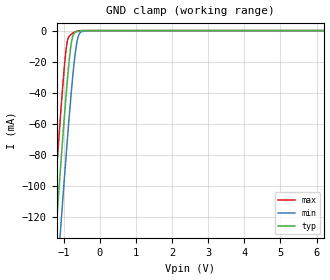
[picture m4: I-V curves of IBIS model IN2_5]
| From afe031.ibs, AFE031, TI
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|   IN2 5V Model
[Model]  IN2_5
Model_type Input
Vinl = 1.5
Vinh = 3.5
|   typ   min   max
|   (nom PVT)   (Fast PVT)   (slow PVT)
C_comp   8.5997880e-13  7.5144900e-13  1.0683370e-12
| Where   nom PVT is  Nominal Process, 5V, 52C
|   Fast PVT is Strong Process, 5.5V, -40C
|   Slow PVT is Weak Process, 4.5V, 150C
[Voltage Range]   5   4.5   5.5
[Temperature Range]   52   150   -40
[Power Clamp Reference]   5   4.5   5.5
[GND Clamp Reference]   0   0   0
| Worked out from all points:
|   GND clamp passes 1 mA (typ) near -0.68 V on its own axis
[GND Clamp]
|   Voltage   I(typ)   I(min)   I(max)
-5V       -1.452A    -1.471A    -1.441A
-1.363V   -178.7mA   -217.8mA   -145.9mA
-1.298V   -156.9mA   -196.2mA   -123.5mA
-1.217V   -130.1mA   -170mA     -96.4mA
-1.092V   -89.47mA   -129.6mA   -55.5mA
-979.9mV  -54.67mA   -94.45mA   -22.43mA
-921.5mV  -37.82mA   -76.87mA   -9.754mA
-788.5mV  -7.817mA   -38.95mA   -2.309mA
-647.5mV  -767.2uA   -9.042mA   -394uA
-561mV    -354uA     -1.782mA   -137.6uA
-352.6mV  -19.74uA   -18.32uA   -23.73uA
10V       0A         0A         0A
[POWER Clamp]
|   SCR cell for ESD function. Effects occurr above VDD x 2
|   Voltage   I(typ)   I(min)   I(max)
-5V       0A         0A         0A
0V        0A         0A         0A
10V       0A         0A         0A
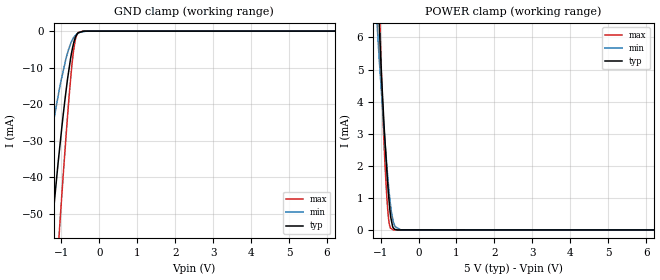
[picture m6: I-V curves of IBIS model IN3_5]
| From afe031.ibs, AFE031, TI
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|   IN3 5V Model
[Model] IN3_5
Model_type Input
Vinl = 1.5
Vinh = 3.5
|   typ   min   max
|   (nom PVT)   (Fast PVT)   (slow PVT)
C_comp   2.4967580e-12  1.9458590e-12  3.0425350e-12
| Where   nom PVT is  Nominal Process, 5V, 52C
|   Fast PVT is Strong Process, 5.5V, -40C
|   Slow PVT is Weak Process, 4.5V, 150C
[Voltage Range]   5   4.5   5.5
[Temperature Range]   52   150   -40
[Power Clamp Reference]   5   4.5   5.5
[GND Clamp Reference]   0   0   0
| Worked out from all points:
|   GND clamp passes 1 mA (typ) near -0.60 V on its own axis
|   POWER clamp passes 1 mA (typ) near -0.78 V on its own axis
[GND Clamp]
|   Voltage   I(typ)   I(min)   I(max)
-5V       -570.3mA   -388.6mA   -720mA
-1.705V   -109.7mA   -60.4mA    -162.3mA
-1.555V   -90.57mA   -48.68mA   -137mA
-1.259V   -54.9mA    -28.09mA   -87.57mA
-1.08V    -35.38mA   -17.42mA   -58.92mA
-1.045V   -31.94mA   -15.43mA   -53.42mA
-850.2mV  -14.08mA   -6.45mA    -24.89mA
-723.3mV  -5.492mA   -2.668mA   -9.289mA
-685mV    -3.657mA   -1.905mA   -5.728mA
-639.5mV  -1.962mA   -1.316mA   -2.701mA
-555.3mV  -436.4uA   -565.7uA   -380.8uA
10V       0A         0A         0A
[POWER Clamp]
|   Voltage   I(typ)   I(min)   I(max)
-5V       168.7mA    134.5mA    216.2mA
-1.1V     8.477mA    6.595mA    10.08mA
-1.054V   6.977mA    5.675mA    8.034mA
-1.029V   6.245mA    5.205mA    6.912mA
-1.013V   5.809mA    4.923mA    6.241mA
-925.6mV  3.647mA    3.387mA    3.134mA
-836.8mV  1.869mA    2.028mA    1.047mA
-769.8mV  812.1uA    1.114mA    178.2uA
-733.4mV  400.6uA    729.6uA    53.42uA
-662.5mV  60.65uA    242.4uA    1.487uA
-468.4mV  1.579uA    2.58uA     1.46uA
10V       0A         0A         0A
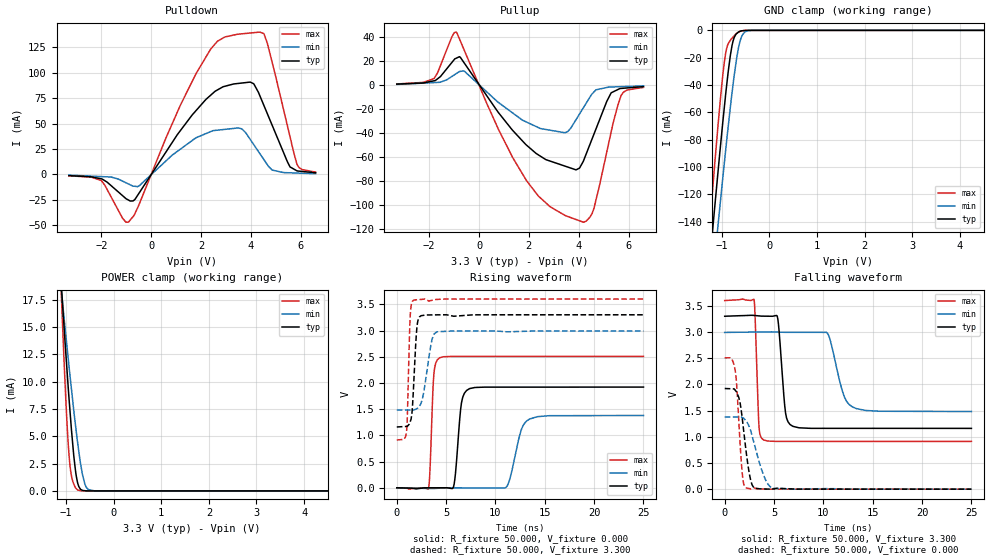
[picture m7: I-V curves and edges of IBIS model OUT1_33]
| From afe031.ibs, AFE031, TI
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|   OUT1 3.3V Model
[Model]  OUT1_33
Model_type   3-state
Polarity   Non-Inverting
Enable   Active-Low
Vmeas = 1.65
Vref = 1.65
Cref = 15pF
Rref = 50
| variable   typ   min   max
|   (nom PVT)   (fast PVT)   (slow PVT)
|C_comp Output in tri-state
|C_comp   1.8415600e-12  1.4370100e-12  2.2641990e-12
|C_comp Output High
C_comp   2.0065070e-12  1.8519680e-12  2.9695770e-12
|C_comp Output Low
|C_comp   1.8415600e-12  1.4370100e-12  2.2641990e-12
| Where   nom PVT is  Nominal Process, 3.3V, 52C
|   Fast PVT is Strong Process, 3.6V, -40C
|   Slow PVT is Weak Process, 3.0V, 150C
[Voltage Range]   3.3   3   3.6
[Temperature Range]   52   150   -40
[Pullup Reference]   3.3   3   3.6
[Pulldown Reference]   0   0   0
[Power Clamp Reference]   3.3   3   3.6
[GND Clamp Reference]   0   0   0
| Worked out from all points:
|   slope of the pulldown table from 0 to 0.495 V, typ, clamps not added: 26.7 ohm
|   slope of the pullup table from 0 to 0.495 V, typ, clamps not added: 33.2 ohm
|   GND clamp passes 1 mA (typ) near -0.64 V on its own axis
|   POWER clamp passes 1 mA (typ) near -0.77 V on its own axis
|   falling waveform, R_fixture 50.000, V_fixture 3.300: 20-80 % time 513ps typ, 1.18ns min, 290ps max; typ from 3.3 V to 1.16 V
|   rising waveform, R_fixture 50.000, V_fixture 0.000: 20-80 % time 500ps typ, 1.02ns min, 299ps max; typ from 0 V to 1.92 V
|   rising waveform, R_fixture 50.000, V_fixture 3.300: 20-80 % time 361ps typ, 734ps min, 231ps max; typ from 1.16 V to 3.3 V
|   falling waveform, R_fixture 50.000, V_fixture 0.000: 20-80 % time 765ps typ, 1.27ns min, 485ps max; typ from 1.92 V to 0 V
[Pulldown]
|   Voltage   I(typ)   I(min)   I(max)
-3.3V     -1.148mA   -651.7uA   -1.255mA
-2.005V   -4.236mA   -2.065mA   -5.91mA
-909.6mV  -25.1mA    -9.305mA   -46.78mA
-491mV    -18.61mA   -11.37mA   -30.01mA
1.155V    42.47mA    24.53mA    67mA
2.371V    77.45mA    41.9mA     122.4mA
3.642V    89.82mA    44.8mA     138.1mA
4.36V     77.57mA    20.63mA    139.9mA
4.66V     59.93mA    9.744mA    129.2mA
5.574V    7.463mA    1.637mA    37.03mA
5.855V    3.549mA    1.397mA    9.994mA
6.6V      1.672mA    769.8uA    2.368mA
[GND Clamp]
|   Voltage   I(typ)   I(min)   I(max)
-3.3V     -996.4mA   -974.3mA   -1.072A
-1.261V   -172mA     -207mA     -145.4mA
-1.196V   -146.9mA   -183.4mA   -117.3mA
-1.079V   -102.9mA   -142.1mA   -68.97mA
-980.7mV  -67.24mA   -108mA     -32.73mA
-918mV    -45.98mA   -87.03mA   -16.26mA
-824mV    -18.83mA   -56.93mA   -7.391mA
-768.6mV  -8.309mA   -40.63mA   -5.048mA
-620mV    -799.1uA   -8.237mA   -684.1uA
-508.1mV  -113.2uA   -1.039mA   -54.85uA
-368.2mV  -29.98uA   -33.32uA   -53.77uA
6.6V      0A         0A         0A
[Pullup]
|   Voltage   I(typ)   I(min)   I(max)
-3.3V     821.6uA    560.4uA    966.4uA
-1.811V   3.556mA    2.098mA    5.376mA
-918mV    22.37mA    9.531mA    44.13mA
-575.9mV  17.9mA     11.38mA    28.21mA
792.2mV   -23.21mA   -14.65mA   -37.35mA
1.893V    -49.73mA   -30.62mA   -79.08mA
3.448V    -67.4mA    -39.59mA   -108.4mA
4.189V    -63.19mA   -18.8mA    -114.1mA
4.609V    -40.93mA   -5.755mA   -102.7mA
5.3V      -6.532mA   -1.562mA   -39.17mA
5.693V    -2.774mA   -1.289mA   -9.028mA
6.6V      -1.247mA   -664.9uA   -1.876mA
[POWER Clamp]
|   Voltage   I(typ)   I(min)   I(max)
-3.3V     184.1mA    127.9mA    289.4mA
-1.099V   18.8mA     18.35mA    17.9mA
-1.077V   17.34mA    17.4mA     15.64mA
-1V       12.29mA    14.04mA    7.901mA
-934.8mV  8.291mA    11.26mA    3.127mA
-878mV    5.172mA    8.968mA    1.198mA
-802.2mV  1.867mA    6.031mA    289uA
-759.4mV  781.9uA    4.492mA    92.02uA
-659.6mV  65.94uA    1.591mA    7.295uA
-603.6mV  19.84uA    621.1uA    7.239uA
-399.7mV  3.531uA    3.881uA    7.034uA
6.6V      0A         0A         0A
[Ramp]
R_load = 50
|   typ   min   max
dV/dt_r   1.15238/4.93956e-010  0.827469/1.00739e-009   1.50375/2.99169e-010
dV/dt_f   1.28388/5.1154e-010   0.922043/1.17816e-009   1.6132/2.87325e-010
[Falling Waveform]
R_fixture = 50.000
V_fixture = 3.300
V_fixture_min = 3.000
V_fixture_max = 3.600
C_fixture = 0.000
|  time   V(typ)   V(min)   V(max)
0s        3.3V       2.991V     3.6V
2.977ns   3.315V     2.998V     3.617V
3.478ns   3.307V     2.999V     1.19V
3.931ns   3.302V     3V         940.6mV
5.337ns   3.291V     2.999V     911.9mV
6.164ns   1.46V      2.993V     911.9mV
6.901ns   1.199V     2.993V     911.8mV
10.41ns   1.161V     2.977V     911.7mV
12.93ns   1.161V     1.572V     911.7mV
25ns      1.16V      1.482V     911.3mV
[Rising Waveform]
R_fixture = 50.000
V_fixture = 0.000
V_fixture_min = 0.000
V_fixture_max = 0.000
C_fixture = 0.000
|  time   V(typ)   V(min)   V(max)
0s        1.734nV    17.7nV     538pV
3.215ns   -590.1uV   -12.93mV   -15.34mV
3.754ns   -338.2uV   -13.77mV   2.157V
4.351ns   -59.32uV   -7.638mV   2.481V
5.746ns   16.23mV    -1.015mV   2.506V
6.563ns   1.627V     -1.713mV   2.506V
7.365ns   1.891V     -2.396mV   2.506V
11.07ns   1.92V      6.88mV     2.506V
13.46ns   1.92V      1.312V     2.506V
25ns      1.921V     1.379V     2.506V
[Rising Waveform]
R_fixture = 50.000
V_fixture = 3.300
V_fixture_min = 3.000
V_fixture_max = 3.600
C_fixture = 0.000
|  time   V(typ)   V(min)   V(max)
0s        1.16V      1.482V     911.3mV
985.8ps   1.17V      1.484V     1.066V
1.362ns   1.261V     1.485V     3.284V
1.71ns    1.963V     1.485V     3.581V
1.975ns   2.909V     1.505V     3.586V
2.187ns   3.22V      1.535V     3.589V
2.718ns   3.29V      1.806V     3.598V
3.564ns   3.298V     2.819V     3.577V
4.059ns   3.299V     2.975V     3.593V
25ns      3.3V       2.991V     3.6V
[Falling Waveform]
R_fixture = 50.000
V_fixture = 0.000
V_fixture_min = 0.000
V_fixture_max = 0.000
C_fixture = 0.000
|  time   V(typ)   V(min)   V(max)
0s        1.921V     1.379V     2.506V
675.3ps   1.916V     1.379V     2.493V
1.058ns   1.891V     1.378V     2.273V
1.448ns   1.737V     1.378V     1.237V
1.781ns   1.348V     1.366V     297mV
2.194ns   684.1mV    1.296V     22.29mV
2.888ns   45.43mV    938.8mV    20.31mV
3.959ns   3.927mV    257.7mV    3.304mV
4.876ns   3.757mV    17.65mV    352.2uV
25ns      1.853nV    17.71nV    612.3pV
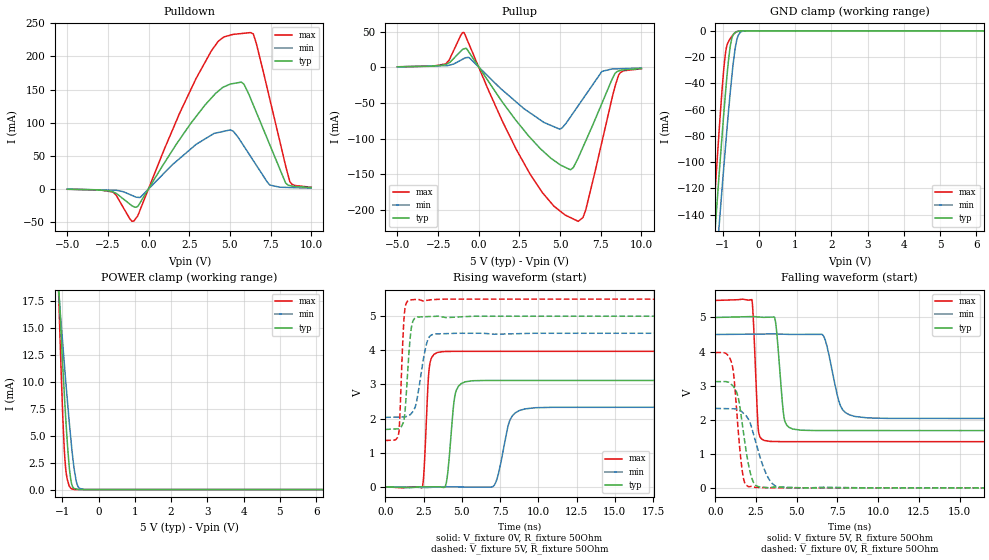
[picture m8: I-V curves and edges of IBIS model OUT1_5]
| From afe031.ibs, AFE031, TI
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|   OUT1 5V Model
[Model]  OUT1_5
Model_type   3-state
Polarity   Non-Inverting
Enable   Active-High
Vmeas = 1.65
Vref = 1.65
Cref = 15pF
Rref = 50
| variable   typ   min   max
|   (nom PVT)   (fast PVT)   (slow PVT)
|C_comp Output in tri-state
|C_comp   1.5706680e-12  1.9286570e-12  1.8438480e-12
|C_comp Output High
C_comp   1.6733830e-12  1.3133470e-12  2.0544670e-12
|C_comp Output Low
|C_comp   1.6733830e-12  1.3133470e-12  2.0544670e-12
| Where   nom PVT is  Nominal Process, 5V, 52C
|   Fast PVT is Strong Process, 5.5V, -40C
|   Slow PVT is Weak Process, 4.5V, 150C
[Voltage Range]   5   4.5   5.5
[Temperature Range]   52   150   -40
[Pullup Reference]   5   4.5   5.5
[Pulldown Reference]   0   0   0
[Power Clamp Reference]   5   4.5   5.5
[GND Clamp Reference]   0   0   0
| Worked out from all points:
|   slope of the pulldown table from 0 to 0.75 V, typ, clamps not added: 24.7 ohm
|   slope of the pullup table from 0 to 0.75 V, typ, clamps not added: 29.3 ohm
|   GND clamp passes 1 mA (typ) near -0.64 V on its own axis
|   POWER clamp passes 1 mA (typ) near -0.77 V on its own axis
|   falling waveform, V_fixture 5V, R_fixture 50Ohm: 20-80 % time 338ps typ, 673ps min, 221ps max; typ from 5 V to 1.68 V
|   rising waveform, V_fixture 0V, R_fixture 50Ohm: 20-80 % time 359ps typ, 642ps min, 244ps max; typ from 0 V to 3.12 V
|   rising waveform, V_fixture 5V, R_fixture 50Ohm: 20-80 % time 306ps typ, 543ps min, 225ps max; typ from 1.68 V to 5 V
|   falling waveform, V_fixture 0V, R_fixture 50Ohm: 20-80 % time 593ps typ, 903ps min, 419ps max; typ from 3.12 V to 0 V
[Pulldown]
|   Voltage   I(typ)   I(min)   I(max)
-5V       -732uA     -486.1uA   -730.4uA
-2.199V   -4.601mA   -2.135mA   -4.991mA
-911.4mV  -27.04mA   -11.2mA    -48.92mA
1.914V    74.74mA    45.87mA    114.5mA
3.828V    136.3mA    80.73mA    207.1mA
5.033V    158.4mA    89.02mA    232.3mA
5.692V    161.3mA    70.81mA    234.7mA
6.266V    137mA      49.15mA    236.2mA
6.625V    115.6mA    35.58mA    219.6mA
7.45V     66.66mA    5.84mA     135.9mA
8.676V    4.936mA    1.921mA    11.49mA
10V       1.829mA    969uA      2.271mA
[GND Clamp]
|   Voltage   I(typ)   I(min)   I(max)
-5V       -1.695A    -1.627A    -1.856A
-1.266V   -173.8mA   -208.6mA   -147.2mA
-1.199V   -148mA     -184.7mA   -118.7mA
-1.085V   -104.9mA   -144.1mA   -71.11mA
-971.7mV  -64.1mA    -105.1mA   -29.92mA
-920.2mV  -46.89mA   -87.87mA   -16.68mA
-782.7mV  -10.44mA   -44.62mA   -5.599mA
-710.2mV  -3.22mA    -25.05mA   -2.818mA
-617.2mV  -734.1uA   -7.912mA   -646.9uA
-513.9mV  -131.8uA   -1.174mA   -67.8uA
-352.9mV  -23.75uA   -22.19uA   -39.54uA
10V       0A         0A         0A
[Pullup]
|   Voltage   I(typ)   I(min)   I(max)
-5V       577.1uA    438.7uA    622.6uA
-2.032V   3.682mA    2.174mA    4.681mA
-920.2mV  25.59mA    12.13mA    48.57mA
1.447V    -48.65mA   -31.81mA   -75.38mA
3.152V    -98.44mA   -63.9mA    -149.6mA
4.988V    -136.4mA   -86.81mA   -201.3mA
5.643V    -143.7mA   -69.48mA   -210.7mA
6.113V    -127.2mA   -53.99mA   -215.9mA
6.572V    -103.5mA   -38.84mA   -200.6mA
7.568V    -50.86mA   -6.016mA   -105.3mA
8.586V    -5.347mA   -2.183mA   -11.93mA
10V       -1.808mA   -1.072mA   -2.13mA
[POWER Clamp]
|   Voltage   I(typ)   I(min)   I(max)
-5V       314.6mA    214.8mA    503.5mA
-1.099V   18.83mA    18.38mA    17.95mA
-1.085V   17.86mA    17.73mA    16.39mA
-989.8mV  11.62mA    13.61mA    7mA
-930.2mV  8.009mA    11.07mA    2.893mA
-862.6mV  4.374mA    8.361mA    927.9uA
-811.9mV  2.2mA      6.372mA    359.9uA
-761.8mV  827.2uA    4.605mA    98.55uA
-671.5mV  101.6uA    1.866mA    6.796uA
-600mV    41.12uA    578.1uA    6.751uA
-387mV    2.931uA    2.767uA    6.615uA
10V       0A         0A         0A
[Ramp]
R_load = 50
|   typ   min   max
dV/dt_r   1.87038/3.56579e-010   1.39853/6.35048e-010   2.38195/2.42285e-010
dV/dt_f   1.99195/3.35036e-010   1.47896/6.66794e-010   2.48696/2.2055e-010
[Falling Waveform]
V_fixture = 5V
V_fixture_min = 4.5V
V_fixture_max = 5.5V
R_fixture = 50Ohm
C_fixture = 0F
|   Time   V(typ)   V(min)   V(max)
0s        5V         4.5V       5.5V
2.24ns    5.026V     4.511V     5.522V
2.633ns   5.015V     4.513V     1.729V
2.994ns   5.004V     4.514V     1.392V
3.647ns   4.983V     4.517V     1.36V
4.214ns   2.072V     4.508V     1.356V
4.759ns   1.726V     4.502V     1.356V
6.621ns   1.681V     4.473V     1.356V
8.576ns   1.681V     2.095V     1.356V
25ns      1.68V      2.035V     1.355V
[Rising Waveform]
V_fixture = 0V
V_fixture_min = 0V
V_fixture_max = 0V
R_fixture = 50Ohm
C_fixture = 0F
|   Time   V(typ)   V(min)   V(max)
0s        1.578nV    10.01nV    578.4pV
2.421ns   -1.432mV   -19.21mV   -13.58mV
2.866ns   -656.9uV   -19.27mV   3.451V
3.386ns   246.6uV    -7.007mV   3.933V
3.942ns   33.63mV    -2.557mV   3.964V
4.549ns   2.666V     -4.545mV   3.969V
5.231ns   3.078V     -6.774mV   3.969V
7.121ns   3.116V     43.07mV    3.969V
9.11ns    3.117V     2.281V     3.969V
25ns      3.117V     2.331V     3.97V
[Rising Waveform]
V_fixture = 5V
V_fixture_min = 4.5V
V_fixture_max = 5.5V
R_fixture = 50Ohm
C_fixture = 0F
|   Time   V(typ)   V(min)   V(max)
0s        1.68V      2.035V     1.355V
880.3ps   1.702V     2.044V     1.564V
948.7ps   1.726V     2.045V     1.992V
1.24ns    2.003V     2.047V     5.021V
1.563ns   4.001V     2.097V     5.472V
1.747ns   4.766V     2.173V     5.481V
1.928ns   4.939V     2.309V     5.488V
2.694ns   4.986V     4.183V     5.462V
3.179ns   4.995V     4.477V     5.489V
25ns      5V         4.5V       5.5V
[Falling Waveform]
|Gnd
V_fixture = 0V
V_fixture_min = 0V
V_fixture_max = 0V
R_fixture = 50Ohm
C_fixture = 0F
|   Time   V(typ)   V(min)   V(max)
0s        3.117V     2.331V     3.97V
1.024ns   3.016V     2.321V     3.623V
1.152ns   2.945V     2.32V      3.189V
1.389ns   2.679V     2.291V     1.757V
1.636ns   1.928V     2.226V     539.9mV
2.03ns    691.1mV    2.013V     33.49mV
2.476ns   70.56mV    1.348V     13.63mV
3.112ns   10.47mV    417mV      6.212mV
3.882ns   24.29mV    26.24mV    509.3uV
25ns      1.84nV     10.02nV    733.8pV
